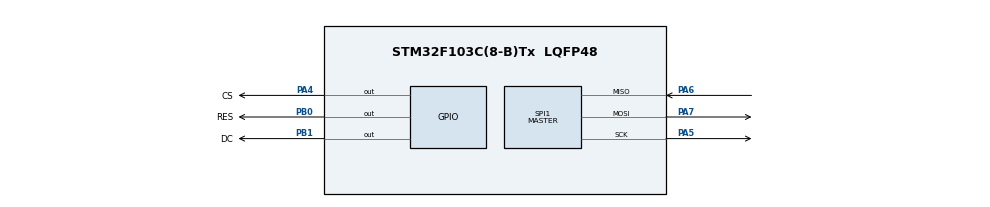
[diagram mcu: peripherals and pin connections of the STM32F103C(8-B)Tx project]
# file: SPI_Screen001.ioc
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Mcu.Family=STM32F1
Mcu.Name=STM32F103C(8-B)Tx
Mcu.Package=LQFP48
NVIC.PriorityGroup=NVIC_PRIORITYGROUP_4
PA13.Mode=Serial_Wire
PA13.Signal=SYS_JTMS-SWDIO
PA14.Mode=Serial_Wire
PA14.Signal=SYS_JTCK-SWCLK
PA4.GPIO_Label=CS
PA4.Signal=GPIO_Output
PA5.Mode=Full_Duplex_Master
PA5.Signal=SPI1_SCK
PA6.Mode=Full_Duplex_Master
PA6.Signal=SPI1_MISO
PA7.Mode=Full_Duplex_Master
PA7.Signal=SPI1_MOSI
PB0.GPIO_Label=RES
PB0.Signal=GPIO_Output
PB1.GPIO_Label=DC
PB1.Signal=GPIO_Output
PD0-OSC_IN.Mode=HSE-External-Oscillator
PD0-OSC_IN.Signal=RCC_OSC_IN
PD1-OSC_OUT.Mode=HSE-External-Oscillator
PD1-OSC_OUT.Signal=RCC_OSC_OUT
ProjectManager.HeapSize=0x200
ProjectManager.StackSize=0x400
ProjectManager.TargetToolchain=STM32CubeIDE
RCC.AHBFreq_Value=72000000
RCC.APB1CLKDivider=RCC_HCLK_DIV2
RCC.APB1Freq_Value=36000000
RCC.APB1TimFreq_Value=72000000
RCC.APB2Freq_Value=72000000
RCC.APB2TimFreq_Value=72000000
RCC.HCLKFreq_Value=72000000
RCC.HSEDivPLL=RCC_HSE_PREDIV_DIV2
RCC.HSE_VALUE=16000000
RCC.PLLMUL=RCC_PLL_MUL9
RCC.PLLSourceVirtual=RCC_PLLSOURCE_HSE
RCC.SYSCLKFreq_VALUE=72000000
RCC.SYSCLKSource=RCC_SYSCLKSOURCE_PLLCLK
RCC.USBFreq_Value=72000000
SPI1.Direction=SPI_DIRECTION_2LINES
SPI1.Mode=SPI_MODE_MASTER
SPI1.VirtualType=VM_MASTER
board=custom

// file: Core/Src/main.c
/* USER CODE BEGIN Header */
/**
  ******************************************************************************
  * @file           : main.c
  * @brief          : Main program body
  ******************************************************************************
  * @attention
  *
  * Copyright (c) 2025 STMicroelectronics.
  * All rights reserved.
  *
  * This software is licensed under terms that can be found in the LICENSE file
  * in the root directory of this software component.
  * If no LICENSE file comes with this software, it is provided AS-IS.
  *
  ******************************************************************************
  */
/* USER CODE END Header */
#include "main.h"

/* USER CODE BEGIN Includes */
#include "z_displ_ST7735.h"
#include "z_displ_ST7735_test.h"
#include "fonts.h"
/* USER CODE END Includes */

SPI_HandleTypeDef hspi1;
DMA_HandleTypeDef hdma_spi1_tx;

void SystemClock_Config(void);
static void MX_GPIO_Init(void);
static void MX_DMA_Init(void);
static void MX_SPI1_Init(void);

int main(void)
{

  /* MCU Configuration--------------------------------------------------------*/

  /* Reset of all peripherals, Initializes the Flash interface and the Systick. */
  HAL_Init();

  /* Configure the system clock */
  SystemClock_Config();

  /* Initialize all configured peripherals */
  MX_GPIO_Init();
  MX_DMA_Init();
  MX_SPI1_Init();
  /* USER CODE BEGIN 2 */

  Displ_Init(Displ_Orientat_0);		// initialize the display and set the initial display orientation (here is orientaton: 0°) - THIS FUNCTION MUST PRECEED ANY OTHER DISPLAY FUNCTION CALL.
  Displ_CLS(BLACK);			// after initialization (above) and before turning on backlight (below), you can draw the initial display appearance. (here I'm just clearing display with a black background)
  Displ_BackLight('I');  			// initialize backlight and turn it on at init level
  /* USER CODE END 2 */

  /* Infinite loop */
  /* USER CODE BEGIN WHILE */
  while (1)
  {
	  Displ_PerfTest();		// shows display graphics and performance
    /* USER CODE END WHILE */

  }
}

void SystemClock_Config(void)
{
  RCC_OscInitTypeDef RCC_OscInitStruct = {0};
  RCC_ClkInitTypeDef RCC_ClkInitStruct = {0};

  /** Initializes the RCC Oscillators according to the specified parameters
  * in the RCC_OscInitTypeDef structure.
  */
  RCC_OscInitStruct.OscillatorType = RCC_OSCILLATORTYPE_HSE;
  RCC_OscInitStruct.HSEState = RCC_HSE_ON;
  RCC_OscInitStruct.HSEPredivValue = RCC_HSE_PREDIV_DIV1;
  RCC_OscInitStruct.HSIState = RCC_HSI_ON;
  RCC_OscInitStruct.PLL.PLLState = RCC_PLL_ON;
  RCC_OscInitStruct.PLL.PLLSource = RCC_PLLSOURCE_HSE;
  RCC_OscInitStruct.PLL.PLLMUL = RCC_PLL_MUL9;
  if (HAL_RCC_OscConfig(&RCC_OscInitStruct) != HAL_OK)
  {
    Error_Handler();
  }

  /** Initializes the CPU, AHB and APB buses clocks
  */
  RCC_ClkInitStruct.ClockType = RCC_CLOCKTYPE_HCLK|RCC_CLOCKTYPE_SYSCLK
                              |RCC_CLOCKTYPE_PCLK1|RCC_CLOCKTYPE_PCLK2;
  RCC_ClkInitStruct.SYSCLKSource = RCC_SYSCLKSOURCE_PLLCLK;
  RCC_ClkInitStruct.AHBCLKDivider = RCC_SYSCLK_DIV1;
  RCC_ClkInitStruct.APB1CLKDivider = RCC_HCLK_DIV2;
  RCC_ClkInitStruct.APB2CLKDivider = RCC_HCLK_DIV1;

  if (HAL_RCC_ClockConfig(&RCC_ClkInitStruct, FLASH_LATENCY_2) != HAL_OK)
  {
    Error_Handler();
  }
}

static void MX_SPI1_Init(void)
{

  /* SPI1 parameter configuration*/
  hspi1.Instance = SPI1;
  hspi1.Init.Mode = SPI_MODE_MASTER;
  hspi1.Init.Direction = SPI_DIRECTION_1LINE;
  hspi1.Init.DataSize = SPI_DATASIZE_8BIT;
  hspi1.Init.CLKPolarity = SPI_POLARITY_LOW;
  hspi1.Init.CLKPhase = SPI_PHASE_1EDGE;
  hspi1.Init.NSS = SPI_NSS_HARD_OUTPUT;
  hspi1.Init.BaudRatePrescaler = SPI_BAUDRATEPRESCALER_32;
  hspi1.Init.FirstBit = SPI_FIRSTBIT_MSB;
  hspi1.Init.TIMode = SPI_TIMODE_DISABLE;
  hspi1.Init.CRCCalculation = SPI_CRCCALCULATION_DISABLE;
  hspi1.Init.CRCPolynomial = 10;
  if (HAL_SPI_Init(&hspi1) != HAL_OK)
  {
    Error_Handler();
  }

}

static void MX_DMA_Init(void)
{

  /* DMA controller clock enable */
  __HAL_RCC_DMA1_CLK_ENABLE();

  /* DMA interrupt init */
  /* DMA1_Channel3_IRQn interrupt configuration */
  HAL_NVIC_SetPriority(DMA1_Channel3_IRQn, 4, 0);
  HAL_NVIC_EnableIRQ(DMA1_Channel3_IRQn);

}

static void MX_GPIO_Init(void)
{
  GPIO_InitTypeDef GPIO_InitStruct = {0};

  /* GPIO Ports Clock Enable */
  __HAL_RCC_GPIOC_CLK_ENABLE();
  __HAL_RCC_GPIOD_CLK_ENABLE();
  __HAL_RCC_GPIOA_CLK_ENABLE();
  __HAL_RCC_GPIOB_CLK_ENABLE();

  /*Configure GPIO pin Output Level */
  HAL_GPIO_WritePin(DISPL_LED_GPIO_Port, DISPL_LED_Pin, GPIO_PIN_RESET);

  /*Configure GPIO pin Output Level */
  HAL_GPIO_WritePin(GPIOB, DISPL_RST_Pin|DISPL_DC_Pin, GPIO_PIN_RESET);

  /*Configure GPIO pin : DISPL_LED_Pin */
  GPIO_InitStruct.Pin = DISPL_LED_Pin;
  GPIO_InitStruct.Mode = GPIO_MODE_OUTPUT_PP;
  GPIO_InitStruct.Pull = GPIO_NOPULL;
  GPIO_InitStruct.Speed = GPIO_SPEED_FREQ_LOW;
  HAL_GPIO_Init(DISPL_LED_GPIO_Port, &GPIO_InitStruct);

  /*Configure GPIO pins : DISPL_RST_Pin DISPL_DC_Pin */
  GPIO_InitStruct.Pin = DISPL_RST_Pin|DISPL_DC_Pin;
  GPIO_InitStruct.Mode = GPIO_MODE_OUTPUT_PP;
  GPIO_InitStruct.Pull = GPIO_NOPULL;
  GPIO_InitStruct.Speed = GPIO_SPEED_FREQ_LOW;
  HAL_GPIO_Init(GPIOB, &GPIO_InitStruct);

}

/* USER CODE BEGIN 4 */

/**
 * @brief Custom delay function using simple loop
 * @param ms: delay time in milliseconds
 * @retval None
 */
void Custom_Delay(uint32_t ms)
{
    // Debug-friendly delay function
    // For STM32F103C8T6 at 72MHz
    // Each iteration takes ~72 cycles (24 NOPs + loop overhead)
    // 72MHz / 72 = 1MHz cycles per iteration
    // For 1ms delay: 1MHz / 1000 = 1000 iterations
    uint32_t iterations = ms * 1000; // Reduced from 24000 to 1000

    for(uint32_t i = 0; i < iterations; i++)
    {
        // Use multiple NOPs to reduce loop count while maintaining timing
        __asm("nop");
        __asm("nop");
        __asm("nop");
        __asm("nop");
        __asm("nop");
        __asm("nop");
        __asm("nop");
        __asm("nop");
        __asm("nop");
        __asm("nop");
        __asm("nop");
        __asm("nop");
        __asm("nop");
        __asm("nop");
        __asm("nop");
        __asm("nop");
        __asm("nop");
        __asm("nop");
        __asm("nop");
        __asm("nop");
        __asm("nop");
        __asm("nop");
        __asm("nop");
        __asm("nop");
        __asm("nop");
    }
}

/**
 * @brief Ultra-light delay function for debugging
 * @param ms: delay time in milliseconds
 * @retval None
 */
void Debug_Delay(uint32_t ms)
{
    // Minimal delay for debugging - very few iterations
    // Prevents debugger timeouts and performance issues
    volatile uint32_t iterations = ms * 100; // Very light for debugging

    while(iterations--)
    {
        // Minimal overhead loop
    }
}

/* USER CODE END 4 */

void Error_Handler(void)
{
  /* USER CODE BEGIN Error_Handler_Debug */
  /* User can add his own implementation to report the HAL error return state */
  __disable_irq();
  while (1)
  {
    /* Error occurred - program halted */
  }
  /* USER CODE END Error_Handler_Debug */
}
